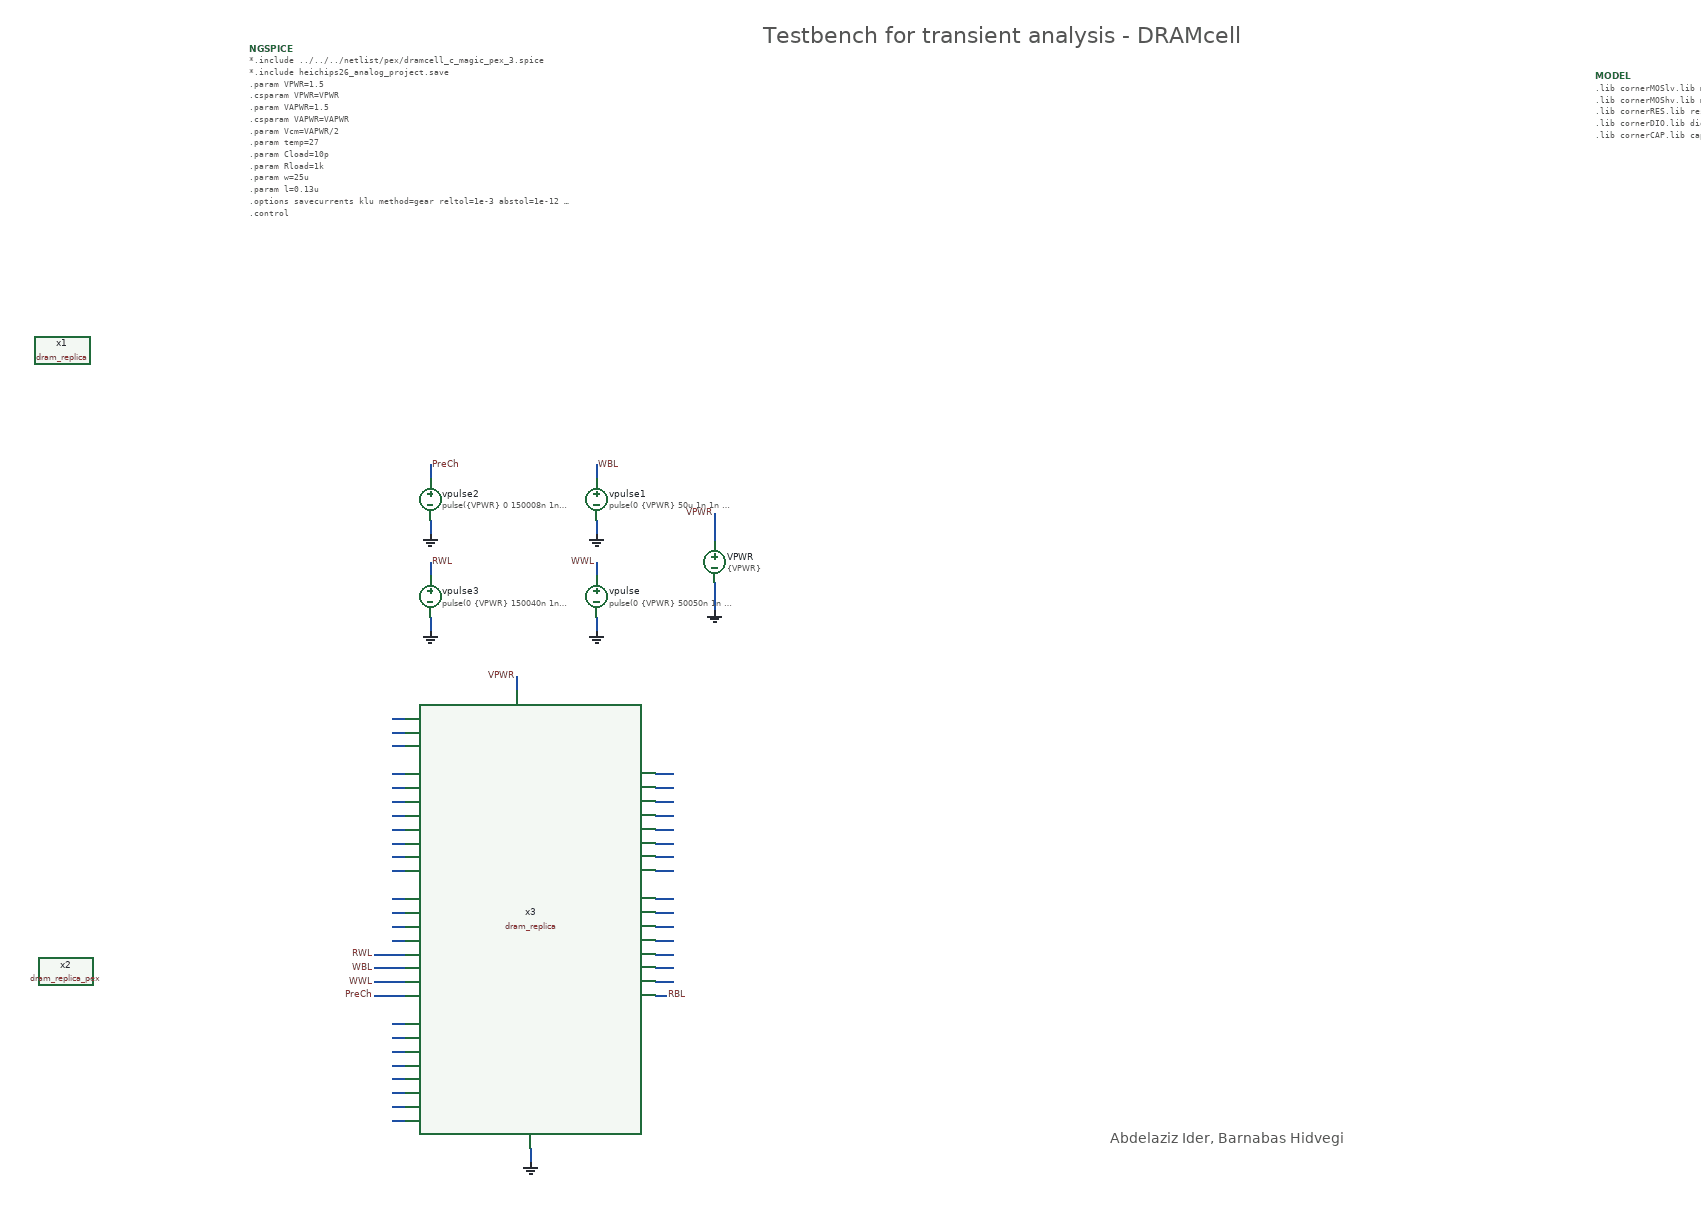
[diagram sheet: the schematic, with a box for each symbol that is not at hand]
v {xschem version=3.4.8RC file_version=1.3}
G {}
K {}
V {}
S {}
F {}
E {}
B 2 1640 -1490 2440 -1090 {flags=graph
y1=0
y2=1.6
ypos1=0
ypos2=2
divy=5
subdivy=1
unity=1
x1=0
x2=0.0008
divx=5
subdivx=1
xlabmag=1.0
ylabmag=1.0


dataset=-1
unitx=1
logx=0
logy=0
color="6 15"
node="RWL
PreCh"
linewidth_mult=6
hilight_wave=2}
B 2 1640 -1040 2440 -640 {flags=graph
y1=-1.5e-05
y2=1.6e-06
ypos1=0
ypos2=2
divy=5
subdivy=1
unity=1
x1=0
x2=0.0008
divx=5
subdivx=1
xlabmag=1.0
ylabmag=1.0
dataset=-1
unitx=1
logx=0
logy=0
autoload=0
rainbow=1
linewidth_mult=6
color=7
node=i(vpwr)
}
B 2 1630 -600 2430 -200 {flags=graph
y1=-0.32
y2=1.5
ypos1=0
ypos2=2
divy=5
subdivy=1
unity=1
x1=0
x2=0.0008
divx=5
subdivx=1
xlabmag=1.0
ylabmag=1.0
dataset=-1
unitx=1
logx=0
logy=0
autoload=0
hilight_wave=-1
color=4
node=RBL
linewidth_mult=6}
B 2 800 -1490 1600 -1090 {flags=graph
y1=0
y2=1.6
ypos1=0
ypos2=2
divy=5
subdivy=1
unity=1
x1=0
x2=0.0008
divx=5
subdivx=1
xlabmag=1.0
ylabmag=1.0


dataset=-1
unitx=1
logx=0
logy=0
color=6
node=WWL
linewidth_mult=6}
B 2 800 -1040 1600 -640 {flags=graph
y1=0
y2=1.6
ypos1=0
ypos2=2
divy=5
subdivy=1
unity=1
x1=0
x2=0.0008
divx=5
subdivx=1
xlabmag=1.0
ylabmag=1.0


dataset=-1
unitx=1
logx=0
logy=0
linewidth_mult=6
color=6
node=WBL}
B 2 800 -600 1600 -200 {flags=graph
y1=-0.21
y2=1.2
ypos1=0
ypos2=2
divy=5
subdivy=1
unity=1
x1=0
x2=0.0008
divx=5
subdivx=1
xlabmag=1.0
ylabmag=1.0


dataset=-1
unitx=1
logx=0
logy=0
linewidth_mult=6
hcursor1_y=0.71029008}
T {Testbench for transient analysis - DRAMcell} 740 -1730 0 0 1 1 {}
T {Abdelaziz Ider, Barnabas Hidvegi} 1240 -140 0 0 0.6 0.6 {}
N 500 -880 500 -860 {lab=GND}
N 500 -1020 500 -1000 {lab=GND}
N 670 -1030 670 -990 {lab=VPWR}
N 670 -930 670 -890 {lab=GND}
N 260 -880 260 -860 {lab=GND}
N 260 -960 260 -940 {lab=RWL}
N 500 -1100 500 -1080 {lab=WBL}
N 500 -960 500 -940 {lab=WWL}
N 260 -1020 260 -1000 {lab=GND}
N 260 -1100 260 -1080 {lab=PreCh}
N 385 -795 385 -775 {lab=VPWR}
N 405 -115 405 -95 {lab=GND}
N 180 -355 225 -355 {lab=WWL}
N 180 -335 225 -335 {lab=PreCh}
N 180 -375 225 -375 {lab=WBL}
N 180 -395 225 -395 {lab=RWL}
N 585 -335 600 -335 {lab=RBL}
N 205 -735 225 -735 {lab=#net1}
N 205 -715 225 -715 {lab=#net2}
N 205 -695 225 -695 {lab=#net3}
N 205 -655 225 -655 {lab=#net4}
N 205 -635 225 -635 {lab=#net5}
N 205 -615 225 -615 {lab=#net6}
N 205 -595 225 -595 {lab=#net7}
N 205 -575 225 -575 {lab=#net8}
N 205 -555 225 -555 {lab=#net9}
N 205 -535 225 -535 {lab=#net10}
N 205 -515 225 -515 {lab=#net11}
N 205 -475 225 -475 {lab=#net12}
N 205 -455 225 -455 {lab=#net13}
N 205 -435 225 -435 {lab=#net14}
N 205 -415 225 -415 {lab=#net15}
N 205 -295 225 -295 {lab=#net16}
N 205 -275 225 -275 {lab=#net17}
N 205 -255 225 -255 {lab=#net18}
N 205 -235 225 -235 {lab=#net19}
N 205 -215 225 -215 {lab=#net20}
N 205 -195 225 -195 {lab=#net21}
N 205 -175 225 -175 {lab=#net22}
N 205 -155 225 -155 {lab=#net23}
N 585 -655 610 -655 {lab=#net24}
N 585 -635 610 -635 {lab=#net25}
N 585 -615 610 -615 {lab=#net26}
N 585 -595 610 -595 {lab=#net27}
N 585 -575 610 -575 {lab=#net28}
N 585 -555 610 -555 {lab=#net29}
N 585 -535 610 -535 {lab=#net30}
N 585 -515 610 -515 {lab=#net31}
N 585 -475 610 -475 {lab=#net32}
N 585 -455 610 -455 {lab=#net33}
N 585 -435 610 -435 {lab=#net34}
N 585 -415 610 -415 {lab=#net35}
N 585 -395 610 -395 {lab=#net36}
N 585 -375 610 -375 {lab=#net37}
N 585 -355 610 -355 {lab=#net38}
C {title-3.sym} 0 0 0 0 {name=l2 author=" " rev=1.0 lock=true}
C {devices/gnd.sym} 500 -860 0 0 {name=l26 lab=GND}
C {devices/vsource.sym} 500 -910 0 1 {name=vpulse spice_ignore=False value="pulse(0 \{VPWR\} 50050n 1n 1n 10n 100u)"
}
C {devices/gnd.sym} 500 -1000 0 1 {name=l53 lab=GND}
C {devices/code_shown.sym} 0 -1700 0 0 {name=NGSPICE
only_toplevel=true 
value="
*.include ../../../netlist/pex/dramcell_c_magic_pex_3.spice
*.include heichips26_analog_project.save
.param VPWR=1.5
.csparam VPWR=VPWR
.param VAPWR=1.5
.csparam VAPWR=VAPWR
.param Vcm=VAPWR/2
.param temp=27
.param Cload=10p
.param Rload=1k
.param w=25u
.param l=0.13u
.options savecurrents klu method=gear reltol=1e-3 abstol=1e-12 gmin=1e-12
.control
save all

* Operating Point Analysis
op
remzerovec
write @schname\\\\.raw
set appendwrite

* Transient Analysis
tran 10n 800u
write @schname\\\\.raw

unset appendwrite
set wr_vecnames
set wr_singlescale
*wrdata ../plot_simulations/data/@schname\\\\.txt

*quit
.endc
"}
C {devices/launcher.sym} 920 -1560 0 0 {name=h2
descr="Simulate" 
tclcommand="xschem save; xschem netlist; xschem simulate"
}
C {devices/launcher.sym} 1660 -1560 0 0 {name=h1
descr="Load waves" 
tclcommand="xschem raw_read $netlist_dir/[file rootname [file tail [xschem get current_name]]].raw tran"
}
C {devices/launcher.sym} 1260 -1560 0 0 {name=h3
descr="Annotate OP" 
tclcommand="set show_hidden_texts 1; xschem annotate_op"
}
C {devices/code_shown.sym} 1940 -1660 0 0 {name=MODEL only_toplevel=true
format="tcleval( @value )"
value="
.lib cornerMOSlv.lib mos_tt
.lib cornerMOShv.lib mos_tt
.lib cornerRES.lib res_typ
.lib cornerDIO.lib dio_tt
.lib cornerCAP.lib cap_typ
"}
C {devices/lab_pin.sym} 180 -355 2 1 {name=l6 sig_type=std_logic lab=WWL}
C {devices/lab_pin.sym} 180 -395 2 1 {name=l7 sig_type=std_logic lab=RWL}
C {devices/vsource.sym} 670 -960 0 0 {name=VPWR value=\{VPWR\}}
C {devices/gnd.sym} 670 -890 0 0 {name=l19 lab=GND}
C {devices/lab_pin.sym} 670 -1030 3 1 {name=l11 sig_type=std_logic lab=VPWR}
C {devices/vsource.sym} 500 -1050 0 1 {name=vpulse1 value="pulse(0 \{VPWR\} 50u 1n 1n 100n 400u)"
}
C {devices/vsource.sym} 260 -910 0 1 {name=vpulse3 spice_ignore=False value="pulse(0 \{VPWR\} 150040n 1n 1n 30n 200u)"
}
C {devices/lab_pin.sym} 260 -960 0 1 {name=l3 sig_type=std_logic lab=RWL}
C {devices/lab_pin.sym} 500 -1100 0 1 {name=l17 sig_type=std_logic lab=WBL}
C {devices/lab_pin.sym} 500 -960 2 1 {name=l18 sig_type=std_logic lab=WWL}
C {devices/lab_pin.sym} 180 -375 2 1 {name=l25 sig_type=std_logic lab=WBL}
C {devices/lab_pin.sym} 385 -795 3 1 {name=l32 sig_type=std_logic lab=VPWR}
C {devices/lab_pin.sym} 600 -335 0 1 {name=l14 sig_type=std_logic lab=RBL}
C {devices/gnd.sym} 260 -860 0 0 {name=l1 lab=GND}
C {devices/vsource.sym} 260 -1050 0 1 {name=vpulse2 spice_ignore=False value="pulse(\{VPWR\} 0 150008n 1n 1n 10n 200u)"
}
C {devices/lab_pin.sym} 260 -1100 0 1 {name=l12 sig_type=std_logic lab=PreCh}
C {devices/gnd.sym} 260 -1000 0 0 {name=l13 lab=GND}
C {devices/lab_pin.sym} 180 -335 2 1 {name=l16 sig_type=std_logic lab=PreCh}
C {devices/gnd.sym} 405 -95 0 0 {name=l5 lab=GND}
C {dram_replica.sym} -270 -1265 0 0 {name=x1
spice_ignore=true}
C {dram_replica_pex.sym} -265 -370 0 0 {name=x2
spice_ignore=true}
C {dram_replica.sym} 405 -435 0 0 {name=x3
}
C {noconn.sym} 205 -735 2 1 {name=l38}
C {noconn.sym} 205 -715 2 1 {name=l4}
C {noconn.sym} 205 -695 2 1 {name=l8}
C {noconn.sym} 205 -655 2 1 {name=l9}
C {noconn.sym} 205 -635 2 1 {name=l10}
C {noconn.sym} 205 -615 2 1 {name=l15}
C {noconn.sym} 205 -595 2 1 {name=l20}
C {noconn.sym} 205 -575 2 1 {name=l21}
C {noconn.sym} 205 -555 2 1 {name=l22}
C {noconn.sym} 205 -535 2 1 {name=l23}
C {noconn.sym} 205 -515 2 1 {name=l24}
C {noconn.sym} 205 -475 2 1 {name=l27}
C {noconn.sym} 205 -455 2 1 {name=l28}
C {noconn.sym} 205 -435 2 1 {name=l29}
C {noconn.sym} 205 -415 2 1 {name=l30}
C {noconn.sym} 205 -295 2 1 {name=l31}
C {noconn.sym} 205 -275 2 1 {name=l33}
C {noconn.sym} 205 -255 2 1 {name=l34}
C {noconn.sym} 205 -235 2 1 {name=l35}
C {noconn.sym} 205 -215 2 1 {name=l36}
C {noconn.sym} 205 -195 2 1 {name=l37}
C {noconn.sym} 205 -175 2 1 {name=l39}
C {noconn.sym} 205 -155 2 1 {name=l40}
C {noconn.sym} 610 -655 2 0 {name=l41}
C {noconn.sym} 610 -635 2 0 {name=l42}
C {noconn.sym} 610 -615 2 0 {name=l43}
C {noconn.sym} 610 -595 2 0 {name=l44}
C {noconn.sym} 610 -575 2 0 {name=l45}
C {noconn.sym} 610 -555 2 0 {name=l46}
C {noconn.sym} 610 -535 2 0 {name=l47}
C {noconn.sym} 610 -515 2 0 {name=l48}
C {noconn.sym} 610 -475 2 0 {name=l49}
C {noconn.sym} 610 -455 2 0 {name=l50}
C {noconn.sym} 610 -435 2 0 {name=l51}
C {noconn.sym} 610 -415 2 0 {name=l52}
C {noconn.sym} 610 -395 2 0 {name=l54}
C {noconn.sym} 610 -375 2 0 {name=l55}
C {noconn.sym} 610 -355 2 0 {name=l56}
